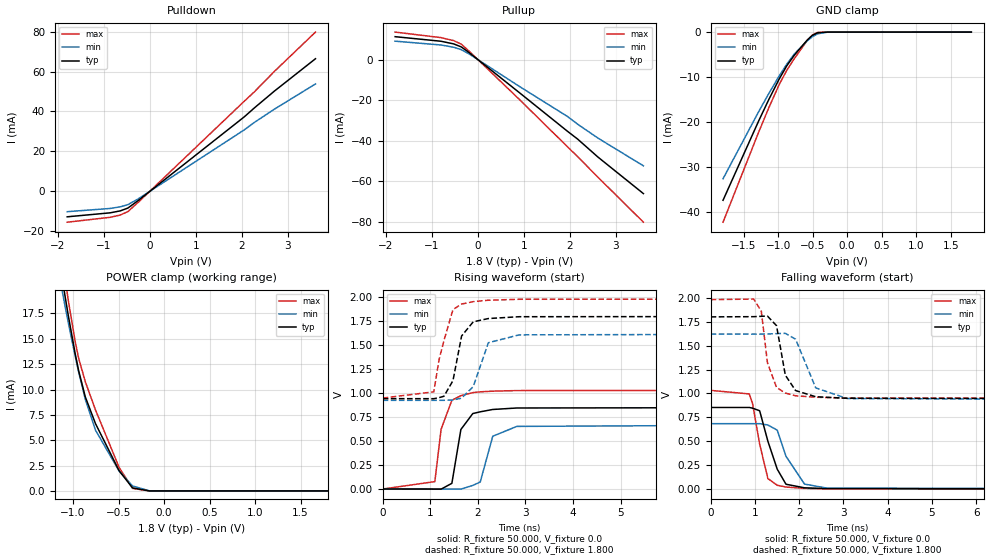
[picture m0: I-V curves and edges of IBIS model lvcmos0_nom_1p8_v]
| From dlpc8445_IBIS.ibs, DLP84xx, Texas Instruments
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|*********************** Begin LVCMOS ***********************************
|   Model Cell1_12
[Model]  lvcmos0_nom_1p8_v
Model_type I/O
Polarity   Non-Inverting
Enable   Active-High
Vinl =  0.580V
Vinh =  1.270V
Vmeas =  0.900V
Cref =  50.000pF
Rref =  1.000M
Vref =  0.0V
C_comp   4.812pF   4.643pF   4.867pF
[Model Spec]
Vinh   1.270V   1.270V   1.270V
Vinl   0.580V   0.580V   0.580V
Vmeas   0.900V   NA   NA
Vref   0.0V   NA   NA
Cref   50.000pF   NA   NA
Rref   1.000M   NA   NA
[Temperature Range]   25.000   0.125k   -40.000
[Voltage Range]   1.800V   1.620V   1.980V
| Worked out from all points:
|   slope of the pulldown table from 0 to 0.27 V, typ, clamps not added: 54.9 ohm
|   slope of the pullup table from 0 to 0.27 V, typ, clamps not added: 55.5 ohm
|   GND clamp passes 1 mA (typ) near -0.53 V on its own axis
|   POWER clamp passes 1 mA (typ) near -0.42 V on its own axis
|   rising waveform, R_fixture 50.000, V_fixture 0.0: 20-80 % time 182ps typ, 226ps min, 212ps max; typ from 0 V to 0.853 V
|   rising waveform, R_fixture 50.000, V_fixture 1.800: 20-80 % time 212ps typ, 265ps min, 259ps max; typ from 0.942 V to 1.8 V
|   falling waveform, R_fixture 50.000, V_fixture 0.0: 20-80 % time 316ps typ, 387ps min, 251ps max; typ from 0.853 V to 0 V
|   falling waveform, R_fixture 50.000, V_fixture 1.800: 20-80 % time 233ps typ, 301ps min, 197ps max; typ from 1.8 V to 0.942 V
[Pulldown]
|Voltage   I(typ)   I(min)   I(max)
-1.8V     -12.84mA   -10.27mA   -15.54mA
-865mV    -10.84mA   -8.642mA   -13.1mA
-645mV    -9.86mA    -7.824mA   -11.94mA
-480mV    -8.448mA   -6.74mA    -10.22mA
-260mV    -4.738mA   -3.909mA   -5.663mA
2.05V     37.29mA    30.77mA    45.13mA
2.27V     41.78mA    34.51mA    49.85mA
2.71V     50.3mA     41.22mA    60.2mA
3.6V      66.47mA    53.82mA    79.83mA
[Pullup]
|Voltage   I(typ)   I(min)   I(max)
-1.8V     11.29mA    9.078mA    13.55mA
-800mV    9.032mA    7.197mA    10.82mA
-525mV    7.725mA    6.075mA    9.333mA
-360mV    6.234mA    4.894mA    7.591mA
-195mV    3.517mA    2.852mA    4.244mA
905mV     -16.31mA   -13.23mA   -19.67mA
1.95V     -35.31mA   -28.02mA   -42.94mA
2.17V     -39.14mA   -31.81mA   -47.78mA
2.61V     -47.96mA   -38.62mA   -57.87mA
3.6V      -65.97mA   -52.3mA    -80.04mA
[GND_clamp]
|Voltage   I(typ)   I(min)   I(max)
-1.8V     -37.47mA   -32.67mA   -42.35mA
-1.282V   -19.75mA   -17.69mA   -22.24mA
-1.134V   -14.95mA   -13.62mA   -16.78mA
-986mV    -10.46mA   -9.778mA   -11.7mA
-875mV    -7.486mA   -7.133mA   -8.501mA
-764mV    -5.097mA   -4.838mA   -5.86mA
-579mV    -1.766mA   -1.945mA   -1.858mA
-505mV    -733.5uA   -1.029mA   -653uA
-431mV    -154.9uA   -383.8uA   -81.65uA
-283mV    -1.21uA    -14.44uA   -257.5nA
1.8V      0A         0A         0A
[POWER_clamp]
|Voltage   I(typ)   I(min)   I(max)
-1.789V   62.42mA    54.67mA    70.27mA
-1.123V   21.2mA     19.93mA    23.18mA
-1.086V   19.15mA    18.18mA    20.87mA
-1.049V   17.17mA    16.48mA    18.65mA
-975mV    13.5mA     13.25mA    14.69mA
-938mV    11.87mA    11.73mA    13.09mA
-864mV    9.251mA    9.016mA    10.75mA
-753mV    6.643mA    5.998mA    7.994mA
-494mV    2mA        1.965mA    2.33mA
-346mV    296uA      492.1uA    251.8uA
-161mV    784nA      8.647uA    252.1nA
1.8V      0A         0A         0A
[Ramp]
| variable   typ   min   max
dV/dt_r   0.512/0.182n   0.411/0.226n   0.619/0.212n
dV/dt_f   0.515/0.233n   0.417/0.300n   0.619/0.197n
R_load = 50.000
[Rising Waveform]
R_fixture= 50.000
V_fixture= 0.0
V_fixture_min= 0.0
V_fixture_max= 0.0
L_fixture= 0.0H
C_fixture= 0.0F
|time   V(typ)   V(min)   V(max)
0s        1.078uV    9.729uV    1.547uV
1.096ns   -782uV     18.33uV    76.96mV
1.227ns   -1.692mV   22.08uV    622.1mV
1.454ns   59.55mV    -910.3uV   925.3mV
1.643ns   620.4mV    -1.351mV   972.7mV
1.894ns   786.7mV    37.36mV    1.005V
2.05ns    804.7mV    73.22mV    1.013V
2.313ns   829mV      550.2mV    1.02V
2.819ns   844.5mV    652.6mV    1.026V
16ns      853.4mV    684.2mV    1.031V
[Rising Waveform]
R_fixture= 50.000
V_fixture= 1.800
V_fixture_min= 1.620
V_fixture_max= 1.980
L_fixture= 0.0H
C_fixture= 0.0F
|time   V(typ)   V(min)   V(max)
0s        941.8mV    924.6mV    948.1mV
1.074ns   941.5mV    924.6mV    1.013V
1.184ns   952.3mV    924.5mV    1.347V
1.287ns   966.8mV    924.6mV    1.548V
1.477ns   1.13V      928mV      1.871V
1.658ns   1.595V     947.1mV    1.928V
1.903ns   1.743V     1.068V     1.953V
2.221ns   1.777V     1.525V     1.968V
2.87ns    1.796V     1.607V     1.978V
16ns      1.8V       1.62V      1.98V
[Falling Waveform]
R_fixture= 50.000
V_fixture= 0.0
V_fixture_min= 0.0
V_fixture_max= 0.0
L_fixture= 0.0H
C_fixture= 0.0F
|time   V(typ)   V(min)   V(max)
0s        853.5mV    684.2mV    1.032V
872ps     853.6mV    684.2mV    994.9mV
947ps     846.3mV    684.2mV    896mV
1.108ns   818.9mV    684.3mV    470.4mV
1.294ns   500.5mV    670.3mV    110.4mV
1.505ns   208.9mV    616.4mV    40.63mV
1.703ns   51.37mV    343.3mV    22.4mV
2.121ns   14.09mV    53.17mV    7.923mV
2.623ns   5.621mV    11.22mV    3.775mV
16ns      23.63uV    47.08uV    11.38uV
[Falling Waveform]
R_fixture= 50.000
V_fixture= 1.800
V_fixture_min= 1.620
V_fixture_max= 1.980
L_fixture= 0.0H
C_fixture= 0.0F
|time   V(typ)   V(min)   V(max)
0s        1.8V       1.62V      1.98V
974ps     1.802V     1.62V      1.986V
1.145ns   1.806V     1.62V      1.86V
1.284ns   1.808V     1.621V     1.32V
1.489ns   1.708V     1.625V     1.063V
1.688ns   1.191V     1.628V     1.004V
1.92ns    1.03V      1.566V     975.7mV
2.375ns   965.5mV    1.058V     960.4mV
3.085ns   949.5mV    946.9mV    951.7mV
16ns      941.8mV    924.6mV    948.1mV
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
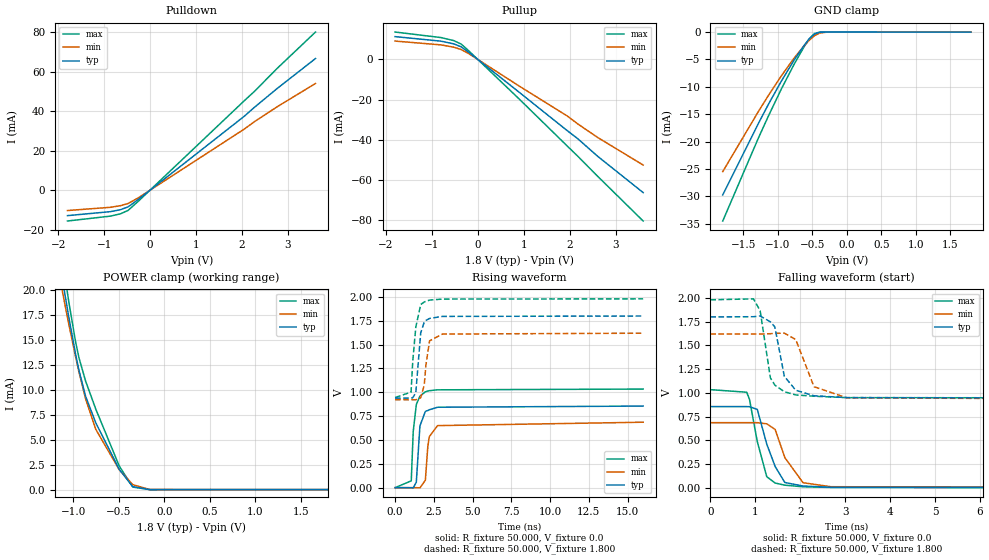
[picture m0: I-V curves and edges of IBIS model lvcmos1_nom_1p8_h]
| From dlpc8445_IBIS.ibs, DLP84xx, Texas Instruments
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|   Model Cell0_12
[Model]  lvcmos1_nom_1p8_h
Model_type I/O
Polarity   Non-Inverting
Enable   Active-High
Vinl =  0.580V
Vinh =  1.270V
Vmeas =  0.900V
Cref =  50.000pF
Rref =  1.000M
Vref =  0.0V
C_comp   5.313pF   5.138pF   5.385pF
[Model Spec]
Vinh   1.270V   1.270V   1.270V
Vinl   0.580V   0.580V   0.580V
Vmeas   0.900V   NA   NA
Vref   0.0V   NA   NA
Cref   50.000pF   NA   NA
Rref   1.000M   NA   NA
[Temperature Range]   25.000   0.125k   -40.000
[Voltage Range]   1.800V   1.620V   1.980V
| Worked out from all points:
|   slope of the pulldown table from 0 to 0.27 V, typ, clamps not added: 54.6 ohm
|   slope of the pullup table from 0 to 0.27 V, typ, clamps not added: 55.2 ohm
|   GND clamp passes 1 mA (typ) near -0.53 V on its own axis
|   POWER clamp passes 1 mA (typ) near -0.42 V on its own axis
|   rising waveform, R_fixture 50.000, V_fixture 0.0: 20-80 % time 211ps typ, 244ps min, 243ps max; typ from 0 V to 0.856 V
|   rising waveform, R_fixture 50.000, V_fixture 1.800: 20-80 % time 252ps typ, 250ps min, 299ps max; typ from 0.939 V to 1.8 V
|   falling waveform, R_fixture 50.000, V_fixture 0.0: 20-80 % time 330ps typ, 410ps min, 275ps max; typ from 0.856 V to 0 V
|   falling waveform, R_fixture 50.000, V_fixture 1.800: 20-80 % time 251ps typ, 328ps min, 207ps max; typ from 1.8 V to 0.939 V
[Pulldown]
|Voltage   I(typ)   I(min)   I(max)
-1.8V     -12.94mA   -10.36mA   -15.67mA
-865mV    -10.92mA   -8.712mA   -13.19mA
-645mV    -9.921mA   -7.883mA   -12.01mA
-480mV    -8.498mA   -6.788mA   -10.28mA
-260mV    -4.765mA   -3.935mA   -5.696mA
2.05V     37.49mA    30.98mA    45.36mA
2.27V     42mA       34.72mA    50.08mA
2.765V    51.55mA    42.28mA    61.75mA
3.6V      66.76mA    54.11mA    80.19mA
[Pullup]
|Voltage   I(typ)   I(min)   I(max)
-1.8V     11.36mA    9.139mA    13.64mA
-800mV    9.085mA    7.243mA    10.88mA
-525mV    7.767mA    6.112mA    9.385mA
-360mV    6.266mA    4.922mA    7.63mA
-195mV    3.534mA    2.867mA    4.265mA
905mV     -16.39mA   -13.3mA    -19.77mA
1.95V     -35.48mA   -28.17mA   -43.14mA
2.17V     -39.32mA   -31.98mA   -48mA
2.61V     -48.19mA   -38.83mA   -58.14mA
3.6V      -66.25mA   -52.54mA   -80.39mA
[GND_clamp]
|Voltage   I(typ)   I(min)   I(max)
-1.8V     -29.72mA   -25.47mA   -34.48mA
-1.282V   -16.66mA   -14.49mA   -19.33mA
-1.134V   -13.12mA   -11.51mA   -15.24mA
-949mV    -8.957mA   -7.99mA    -10.38mA
-764mV    -5.113mA   -4.751mA   -5.884mA
-616mV    -2.396mA   -2.468mA   -2.614mA
-542mV    -1.209mA   -1.466mA   -1.198mA
-468mV    -377uA     -665.7uA   -275.2uA
-394mV    -51.53uA   -194.9uA   -18.39uA
-283mV    -1.21uA    -14.44uA   -257.1nA
1.8V      0A         0A         0A
[POWER_clamp]
|Voltage   I(typ)   I(min)   I(max)
-1.789V   62.53mA    54.94mA    70.53mA
-1.123V   21.33mA    20.06mA    23.4mA
-1.086V   19.29mA    18.31mA    21.08mA
-1.049V   17.31mA    16.6mA     18.84mA
-975mV    13.62mA    13.35mA    14.86mA
-938mV    11.99mA    11.83mA    13.25mA
-864mV    9.348mA    9.1mA      10.88mA
-753mV    6.713mA    6.058mA    8.091mA
-494mV    2.023mA    1.988mA    2.359mA
-346mV    298.7uA    497uA      254.3uA
-161mV    783.7nA    8.652uA    251.7nA
1.8V      0A         0A         0A
[Ramp]
| variable   typ   min   max
dV/dt_r   0.513/0.211n   0.412/0.244n   0.620/0.243n
dV/dt_f   0.516/0.251n   0.419/0.328n   0.621/0.207n
R_load = 50.000
[Rising Waveform]
R_fixture= 50.000
V_fixture= 0.0
V_fixture_min= 0.0
V_fixture_max= 0.0
L_fixture= 0.0H
C_fixture= 0.0F
|time   V(typ)   V(min)   V(max)
0s        1.069uV    9.644uV    1.533uV
1.042ns   -550.6uV   -39.1uV    71.47mV
1.169ns   -2.02mV    38.97uV    590.1mV
1.368ns   57.43mV    -459.9uV   872.2mV
1.601ns   647mV      -1.899mV   959.7mV
1.952ns   800mV      77.75mV    1.005V
2.108ns   808.7mV    428.3mV    1.013V
2.203ns   816.8mV    534.2mV    1.017V
2.74ns    843.4mV    650.7mV    1.026V
16ns      855.7mV    686.4mV    1.034V
[Rising Waveform]
R_fixture= 50.000
V_fixture= 1.800
V_fixture_min= 1.620
V_fixture_max= 1.980
L_fixture= 0.0H
C_fixture= 0.0F
|time   V(typ)   V(min)   V(max)
0s        939.3mV    921.9mV    945.2mV
1.028ns   939mV      921.9mV    1.002V
1.135ns   942mV      921.9mV    1.319V
1.334ns   996.5mV    921.7mV    1.683V
1.653ns   1.624V     942.7mV    1.921V
1.88ns    1.737V     1.077V     1.947V
1.988ns   1.754V     1.288V     1.955V
2.224ns   1.775V     1.54V      1.967V
3.051ns   1.796V     1.611V     1.978V
16ns      1.8V       1.62V      1.98V
[Falling Waveform]
R_fixture= 50.000
V_fixture= 0.0
V_fixture_min= 0.0
V_fixture_max= 0.0
L_fixture= 0.0H
C_fixture= 0.0F
|time   V(typ)   V(min)   V(max)
0s        855.7mV    686.4mV    1.034V
810ps     855.8mV    686.4mV    1.007V
872ps     854.4mV    686.4mV    931.8mV
1.045ns   826.4mV    686.4mV    488.2mV
1.256ns   460.3mV    674.4mV    117.5mV
1.443ns   224.5mV    614.9mV    50.69mV
1.659ns   56.17mV    318mV      28.02mV
2.064ns   19.2mV     54.06mV    11.11mV
2.685ns   6.268mV    11.87mV    4.148mV
16ns      29.74uV    58.99uV    16.59uV
[Falling Waveform]
R_fixture= 50.000
V_fixture= 1.800
V_fixture_min= 1.620
V_fixture_max= 1.980
L_fixture= 0.0H
C_fixture= 0.0F
|time   V(typ)   V(min)   V(max)
0s        1.8V       1.62V      1.98V
960ps     1.802V     1.62V      1.99V
1.109ns   1.81V      1.62V      1.865V
1.337ns   1.748V     1.623V     1.158V
1.436ns   1.695V     1.627V     1.082V
1.647ns   1.175V     1.629V     1.012V
1.901ns   1.028V     1.562V     978.5mV
2.308ns   969.5mV    1.065V     964.9mV
3.037ns   950.4mV    947.8mV    949.9mV
16ns      939.3mV    921.9mV    945.2mV
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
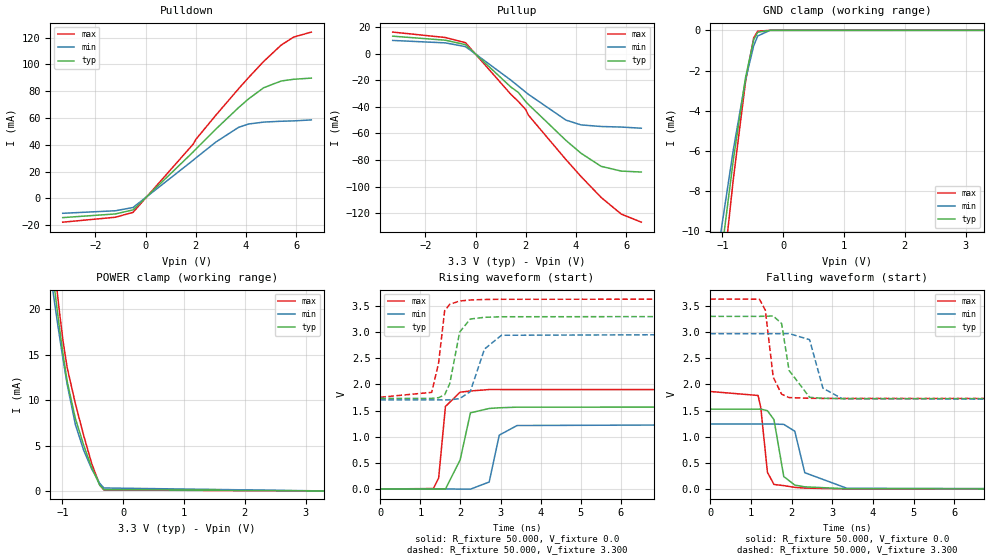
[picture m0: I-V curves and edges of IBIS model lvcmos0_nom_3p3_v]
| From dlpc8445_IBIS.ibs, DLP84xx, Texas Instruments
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|   Model Cell0_12  (lvcmos0_nom_3p3_v)
[Model]  lvcmos0_nom_3p3_v
Model_type I/O
Polarity   Non-Inverting
Enable   Active-High
Vinl =  0.800V
Vinh =  2.000V
Vmeas =  1.650V
Cref =  50.000pF
Rref =  1.000M
Vref =  0.0V
C_comp   3.777pF   3.679pF   3.786pF
[Model Spec]
Vinh   2.000V   2.000V   2.000V
Vinl   0.800V   0.800V   0.800V
Vmeas   1.650V   NA   NA
Vref   0.0V   NA   NA
Cref   50.000pF   NA   NA
Rref   1.000M   NA   NA
[Temperature Range]   25.000   0.125k   -40.000
[Voltage Range]   3.300V   2.970V   3.630V
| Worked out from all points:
|   slope of the pulldown table from 0 to 0.495 V, typ, clamps not added: 55.2 ohm
|   slope of the pullup table from 0 to 0.495 V, typ, clamps not added: 56 ohm
|   GND clamp passes 1 mA (typ) near -0.53 V on its own axis
|   POWER clamp passes 1 mA (typ) near -0.41 V on its own axis
|   rising waveform, R_fixture 50.000, V_fixture 0.0: 20-80 % time 146ps typ, 184ps min, 126ps max; typ from 0 V to 1.57 V
|   rising waveform, R_fixture 50.000, V_fixture 3.300: 20-80 % time 233ps typ, 344ps min, 178ps max; typ from 1.73 V to 3.3 V
|   falling waveform, R_fixture 50.000, V_fixture 0.0: 20-80 % time 183ps typ, 274ps min, 143ps max; typ from 1.53 V to 0 V
|   falling waveform, R_fixture 50.000, V_fixture 3.300: 20-80 % time 197ps typ, 244ps min, 173ps max; typ from 3.3 V to 1.73 V
[Pulldown]
|Voltage   I(typ)   I(min)   I(max)
-3.3V     -14.43mA   -11.2mA    -17.85mA
-1.2V     -11.68mA   -9.31mA    -14.14mA
-500mV    -8.658mA   -6.872mA   -10.51mA
1.9V      34.74mA    28.52mA    40.59mA
2V        36.71mA    30.11mA    43.98mA
2.8V      51.73mA    42.05mA    62.12mA
3.7V      67.72mA    52.98mA    81.78mA
4.1V      74.26mA    55.5mA     90.2mA
4.7V      82.59mA    56.94mA    102.2mA
5.4V      87.66mA    57.58mA    114.5mA
5.9V      88.95mA    57.85mA    120.5mA
6.6V      89.82mA    58.57mA    124.2mA
[Pullup]
|Voltage   I(typ)   I(min)   I(max)
-3.3V     13.04mA    9.833mA    16.11mA
-1.2V     10.02mA    7.999mA    12.03mA
-400mV    6.652mA    5.179mA    8.12mA
1.4V      -25.1mA    -19.92mA   -30.54mA
1.7V      -29.16mA   -24.48mA   -35.98mA
2V        -36.26mA   -29.09mA   -42.12mA
2.1V      -38.15mA   -30.59mA   -46.21mA
3.6V      -65.29mA   -50.02mA   -79.72mA
4.2V      -74.92mA   -53.61mA   -92.4mA
5V        -84.75mA   -54.81mA   -108.1mA
5.8V      -88.3mA    -55.23mA   -120.6mA
6.6V      -89.04mA   -56.1mA    -126.7mA
[GND_clamp]
|Voltage   I(typ)   I(min)   I(max)
-3.3V     -92.25mA   -61.53mA   -135.9mA
-1.29V    -17.92mA   -15.4mA    -21mA
-1.223V   -16.31mA   -14.07mA   -19.04mA
-1.156V   -14.64mA   -12.74mA   -17.03mA
-1.089V   -12.94mA   -11.36mA   -15.03mA
-1.022V   -11.25mA   -9.966mA   -13.05mA
-821mV    -6.443mA   -5.947mA   -7.408mA
-620mV    -2.35mA    -2.459mA   -2.549mA
-486mV    -478.2uA   -770.4uA   -381uA
-419mV    -94.76uA   -279.9uA   -43.05uA
-218mV    -247.6nA   -2.806uA   -222.6nA
3.3V      0A         0A         0A
[POWER_clamp]
|Voltage   I(typ)   I(min)   I(max)
-3.266V   160.8mA    138.4mA    183mA
-1.189V   25.61mA    23.56mA    28.39mA
-1.122V   21.86mA    20.38mA    24.11mA
-1.055V   18.27mA    17.32mA    20.04mA
-988mV    14.94mA    14.4mA     16.4mA
-921mV    12.03mA    11.7mA     13.54mA
-787mV    7.978mA    7.312mA    9.618mA
-653mV    5.091mA    4.523mA    6.167mA
-519mV    2.551mA    2.434mA    3.033mA
-385mV    631.1uA    830.4uA    645.1uA
-318mV    149.6uA    325.9uA    103.4uA
3.3V      0A         0A         0A
[Ramp]
| variable   typ   min   max
dV/dt_r   0.941/0.146n   0.748/0.185n   1.140/0.126n
dV/dt_f   0.945/0.197n   0.760/0.244n   1.139/0.173n
R_load = 50.000
[Rising Waveform]
R_fixture= 50.000
V_fixture= 0.0
V_fixture_min= 0.0
V_fixture_max= 0.0
L_fixture= 0.0H
C_fixture= 0.0F
|time   V(typ)   V(min)   V(max)
0s        2.51uV     11.6uV     3.016uV
1.324ns   -356.5uV   -108uV     8.56mV
1.456ns   -1.554mV   -76.22uV   210.8mV
1.625ns   -2.812mV   4.284uV    1.577V
1.992ns   557.1mV    -1.523mV   1.851V
2.248ns   1.455V     -3.28mV    1.873V
2.716ns   1.539V     133.3mV    1.901V
2.967ns   1.552V     1.029V     1.901V
3.41ns    1.564V     1.213V     1.9V
16ns      1.569V     1.247V     1.9V
[Rising Waveform]
R_fixture= 50.000
V_fixture= 3.300
V_fixture_min= 2.970
V_fixture_max= 3.630
L_fixture= 0.0H
C_fixture= 0.0F
|time   V(typ)   V(min)   V(max)
0s        1.732V     1.703V     1.754V
1.283ns   1.732V     1.703V     1.847V
1.455ns   1.745V     1.703V     2.411V
1.606ns   1.801V     1.703V     3.409V
1.733ns   2.014V     1.703V     3.53V
1.979ns   2.998V     1.727V     3.593V
2.243ns   3.248V     1.86V      3.612V
2.598ns   3.281V     2.674V     3.622V
3.022ns   3.292V     2.938V     3.626V
16ns      3.3V       2.97V      3.63V
[Falling Waveform]
R_fixture= 50.000
V_fixture= 0.0
V_fixture_min= 0.0
V_fixture_max= 0.0
L_fixture= 0.0H
C_fixture= 0.0F
|time   V(typ)   V(min)   V(max)
0s        1.528V     1.244V     1.865V
1.176ns   1.528V     1.244V     1.789V
1.243ns   1.529V     1.244V     1.555V
1.406ns   1.498V     1.244V     322mV
1.567ns   1.328V     1.244V     89.86mV
1.808ns   240.8mV    1.237V     67.61mV
2.079ns   78.11mV    1.107V     34.73mV
2.325ns   44.5mV     314.6mV    20.58mV
3.364ns   7.548mV    16.34mV    4.321mV
16ns      26.1uV     54.9uV     16.38uV
[Falling Waveform]
R_fixture= 50.000
V_fixture= 3.300
V_fixture_min= 2.970
V_fixture_max= 3.630
L_fixture= 0.0H
C_fixture= 0.0F
|time   V(typ)   V(min)   V(max)
0s        3.3V       2.97V      3.63V
1.211ns   3.3V       2.97V      3.627V
1.354ns   3.302V     2.97V      3.418V
1.549ns   3.307V     2.97V      2.137V
1.755ns   3.162V     2.97V      1.814V
1.938ns   2.268V     2.972V     1.749V
2.444ns   1.753V     2.854V     1.735V
2.771ns   1.735V     1.928V     1.733V
3.245ns   1.729V     1.728V     1.732V
16ns      1.725V     1.703V     1.731V
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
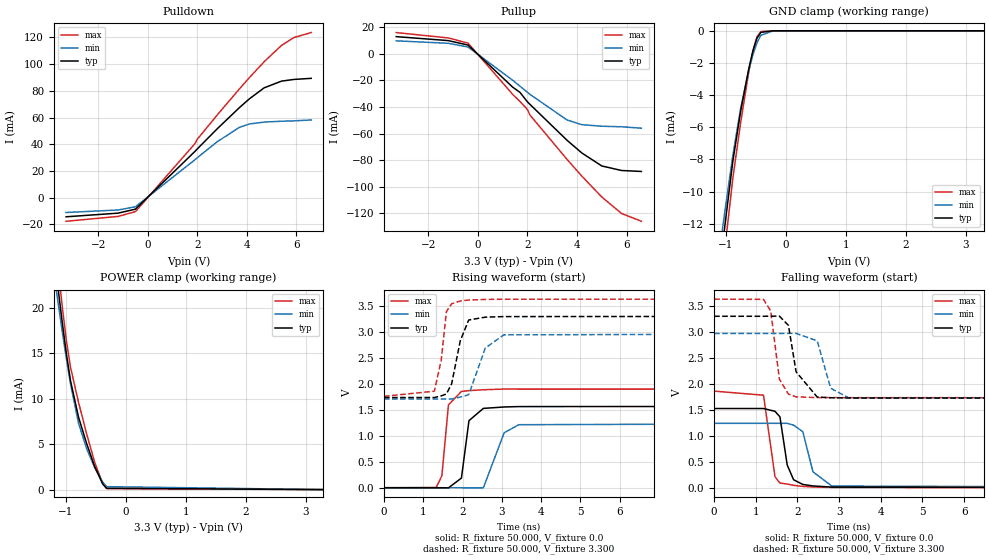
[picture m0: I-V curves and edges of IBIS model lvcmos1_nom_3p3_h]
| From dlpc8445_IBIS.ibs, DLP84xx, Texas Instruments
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|   Model Cell1_12 (lvcmos0_nom_3p3_h)
[Model]  lvcmos1_nom_3p3_h
Model_type I/O
Polarity   Non-Inverting
Enable   Active-High
Vinl =  0.800V
Vinh =  2.000V
Vmeas =  1.650V
Cref =  50.000pF
Rref =  1.000M
Vref =  0.0V
C_comp   3.477pF   3.396pF   3.491pF
[Model Spec]
Vinh   2.000V   2.000V   2.000V
Vinl   0.800V   0.800V   0.800V
Vmeas   1.650V   NA   NA
Vref   0.0V   NA   NA
Cref   50.000pF   NA   NA
Rref   1.000M   NA   NA
[Temperature Range]   25.000   0.125k   -40.000
[Voltage Range]   3.300V   2.970V   3.630V
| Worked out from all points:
|   slope of the pulldown table from 0 to 0.495 V, typ, clamps not added: 55.5 ohm
|   slope of the pullup table from 0 to 0.495 V, typ, clamps not added: 56.3 ohm
|   GND clamp passes 1 mA (typ) near -0.53 V on its own axis
|   POWER clamp passes 1 mA (typ) near -0.41 V on its own axis
|   rising waveform, R_fixture 50.000, V_fixture 0.0: 20-80 % time 146ps typ, 186ps min, 122ps max; typ from 0 V to 1.57 V
|   rising waveform, R_fixture 50.000, V_fixture 3.300: 20-80 % time 267ps typ, 326ps min, 182ps max; typ from 1.74 V to 3.3 V
|   falling waveform, R_fixture 50.000, V_fixture 0.0: 20-80 % time 192ps typ, 269ps min, 143ps max; typ from 1.53 V to 0 V
|   falling waveform, R_fixture 50.000, V_fixture 3.300: 20-80 % time 196ps typ, 244ps min, 171ps max; typ from 3.3 V to 1.73 V
[Pulldown]
|Voltage   I(typ)   I(min)   I(max)
-3.3V     -14.32mA   -11.11mA   -17.7mA
-1.2V     -11.6mA    -9.232mA   -14.04mA
-500mV    -8.607mA   -6.824mA   -10.44mA
1.9V      34.57mA    28.35mA    40.36mA
2V        36.53mA    29.93mA    43.75mA
2.8V      51.5mA     41.81mA    61.82mA
3.7V      67.42mA    52.67mA    81.42mA
4.1V      73.95mA    55.17mA    89.82mA
4.7V      82.24mA    56.59mA    101.8mA
5.4V      87.25mA    57.22mA    114mA
5.9V      88.51mA    57.49mA    119.9mA
6.6V      89.34mA    58.18mA    123.6mA
[Pullup]
|Voltage   I(typ)   I(min)   I(max)
-3.3V     12.95mA    9.779mA    16mA
-1.2V     9.962mA    7.949mA    11.96mA
-400mV    6.618mA    5.149mA    8.078mA
1.4V      -24.98mA   -19.81mA   -30.39mA
1.7V      -29.02mA   -24.35mA   -35.81mA
2V        -36.09mA   -28.93mA   -41.92mA
2.1V      -37.97mA   -30.43mA   -45.99mA
3.6V      -65.01mA   -49.76mA   -79.37mA
4.2V      -74.58mA   -53.26mA   -92.01mA
5V        -84.28mA   -54.42mA   -107.6mA
5.8V      -87.71mA   -54.84mA   -120mA
6.6V      -88.42mA   -55.9mA    -125.9mA
[GND_clamp]
|Voltage   I(typ)   I(min)   I(max)
-3.3V     -114.1mA   -80.88mA   -158.6mA
-1.156V   -16.62mA   -15.01mA   -18.72mA
-1.089V   -14.37mA   -13.14mA   -16.14mA
-1.022V   -12.18mA   -11.28mA   -13.64mA
-888mV    -8.14mA    -7.772mA   -9.194mA
-754mV    -4.947mA   -4.759mA   -5.645mA
-620mV    -2.339mA   -2.447mA   -2.536mA
-553mV    -1.267mA   -1.515mA   -1.267mA
-486mV    -477.2uA   -767.9uA   -380.3uA
-419mV    -94.7uA    -279.4uA   -43.03uA
-218mV    -245.2nA   -2.799uA   -220nA
3.3V      0A         0A         0A
[POWER_clamp]
|Voltage   I(typ)   I(min)   I(max)
-3.266V   165.6mA    138.1mA    194.5mA
-1.189V   25.48mA    23.4mA     28.2mA
-1.122V   21.74mA    20.24mA    23.93mA
-1.055V   18.16mA    17.19mA    19.88mA
-988mV    14.83mA    14.29mA    16.26mA
-921mV    11.95mA    11.61mA    13.44mA
-787mV    7.95mA     7.279mA    9.582mA
-653mV    5.075mA    4.507mA    6.145mA
-519mV    2.545mA    2.428mA    3.024mA
-385mV    630.2uA    829uA      644.1uA
-318mV    149.6uA    325.6uA    103.3uA
3.3V      0A         0A         0A
[Ramp]
| variable   typ   min   max
dV/dt_r   0.940/0.146n   0.746/0.187n   1.139/0.122n
dV/dt_f   0.943/0.196n   0.757/0.244n   1.137/0.172n
R_load = 50.000
[Rising Waveform]
R_fixture= 50.000
V_fixture= 0.0
V_fixture_min= 0.0
V_fixture_max= 0.0
L_fixture= 0.0H
C_fixture= 0.0F
|time   V(typ)   V(min)   V(max)
0s        2.541uV    11.85uV    3.103uV
1.326ns   -445uV     -16.52uV   3.549mV
1.474ns   -1.635mV   -103.4uV   228.6mV
1.642ns   -2.598mV   3.263uV    1.595V
1.972ns   185.5mV    -1.211mV   1.853V
2.164ns   1.291V     -1.915mV   1.869V
2.53ns    1.527V     -1.5mV     1.886V
3.06ns    1.554V     1.058V     1.899V
3.432ns   1.562V     1.213V     1.898V
16ns      1.566V     1.243V     1.898V
[Rising Waveform]
R_fixture= 50.000
V_fixture= 3.300
V_fixture_min= 2.970
V_fixture_max= 3.630
L_fixture= 0.0H
C_fixture= 0.0F
|time   V(typ)   V(min)   V(max)
0s        1.736V     1.708V     1.759V
1.282ns   1.736V     1.708V     1.858V
1.456ns   1.767V     1.707V     2.445V
1.59ns    1.805V     1.708V     3.39V
1.723ns   2V         1.707V     3.54V
1.943ns   2.829V     1.746V     3.595V
2.157ns   3.228V     1.789V     3.612V
2.58ns    3.283V     2.689V     3.624V
3.051ns   3.294V     2.942V     3.628V
16ns      3.3V       2.97V      3.63V
[Falling Waveform]
R_fixture= 50.000
V_fixture= 0.0
V_fixture_min= 0.0
V_fixture_max= 0.0
L_fixture= 0.0H
C_fixture= 0.0F
|time   V(typ)   V(min)   V(max)
0s        1.526V     1.241V     1.861V
1.186ns   1.526V     1.241V     1.782V
1.462ns   1.472V     1.241V     213.4mV
1.58ns    1.366V     1.241V     92.02mV
1.755ns   439.3mV    1.241V     74.2mV
1.908ns   156.2mV    1.206V     48.21mV
2.13ns    65.18mV    1.08V      28.03mV
2.372ns   37.25mV    310mV      16.32mV
2.823ns   14.64mV    35.14mV    7.544mV
16ns      23.35uV    46.91uV    15.53uV
[Falling Waveform]
R_fixture= 50.000
V_fixture= 3.300
V_fixture_min= 2.970
V_fixture_max= 3.630
L_fixture= 0.0H
C_fixture= 0.0F
|time   V(typ)   V(min)   V(max)
0s        3.3V       2.97V      3.63V
1.186ns   3.3V       2.97V      3.625V
1.36ns    3.302V     2.97V      3.399V
1.566ns   3.303V     2.97V      2.093V
1.784ns   3.125V     2.971V     1.804V
1.968ns   2.232V     2.971V     1.75V
2.474ns   1.747V     2.828V     1.736V
2.799ns   1.733V     1.915V     1.736V
3.235ns   1.729V     1.729V     1.735V
16ns      1.728V     1.708V     1.735V
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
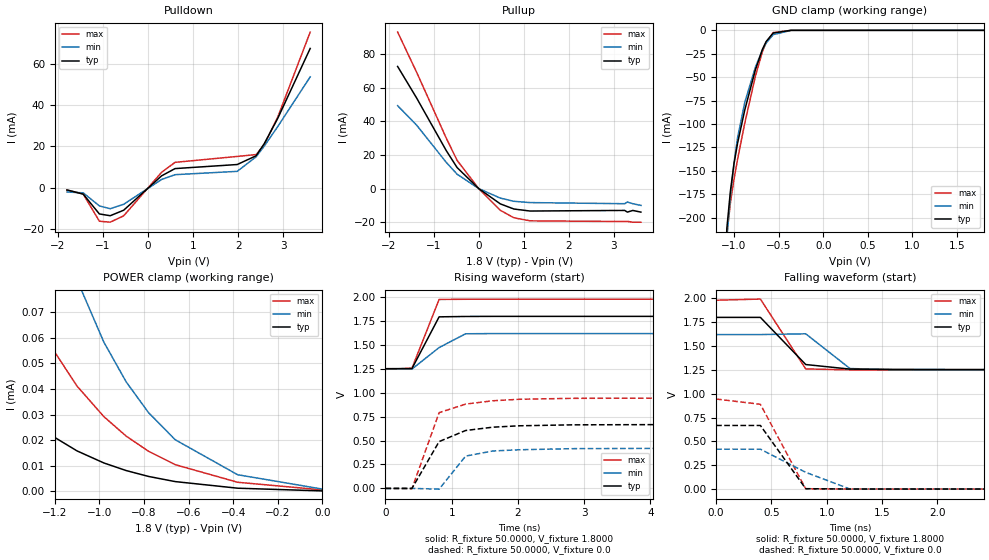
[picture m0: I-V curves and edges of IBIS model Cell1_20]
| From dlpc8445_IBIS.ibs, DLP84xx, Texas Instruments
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|   Model Cell1_20
[Model]  Cell1_20
Model_type I/O
Polarity   Non-Inverting
Enable   Active-Low
Vinl =   0.6300V
Vinh =   1.1700V
Vmeas =  0.9000V
Cref =   50.0000pF
Rref =   1.0000M
Vref =   0.0V
C_comp   1.0153pF   1.0049pF   1.1914pF
[Model Spec]
Vinl 0.63V 0.567V 0.693V
Vinh 1.17V 1.053V 1.287V
[Temperature Range]   25.0000   0.1250k   -40.0000
[Voltage Range]   1.8000V   1.6200V   1.9800V
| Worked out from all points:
|   slope of the pulldown table from 0 to 0.27 V, typ, clamps not added: 51.1 ohm
|   slope of the pullup table from 0 to 0.27 V, typ, clamps not added: 48.4 ohm
|   GND clamp passes 1 mA (typ) near -0.52 V on its own axis
|   rising waveform, R_fixture 50.0000, V_fixture 1.8000: 20-80 % time 249ps typ, 476ps min, 251ps max; typ from 1.25 V to 1.8 V
|   rising waveform, R_fixture 50.0000, V_fixture 0.0: 20-80 % time 452ps typ, 291ps min, 292ps max; typ from 0 V to 0.668 V
|   falling waveform, R_fixture 50.0000, V_fixture 1.8000: 20-80 % time 273ps typ, 245ps min, 247ps max; typ from 1.8 V to 1.25 V
|   falling waveform, R_fixture 50.0000, V_fixture 0.0: 20-80 % time 248ps typ, 480ps min, 262ps max; typ from 0.668 V to 0 V
[Pulldown]
|Voltage   I(typ)   I(min)   I(max)
-1.8V     -1mA       -2mA       -1mA
-1.44V    -3mA       -2.4mA     -3mA
-1.08V    -12.6mA    -8.7mA     -16.1mA
-840mV    -13.46mA   -10.08mA   -16.58mA
-540mV    -10.79mA   -7.914mA   -13.49mA
300mV     5.805mA    4.046mA    7.496mA
600mV     9.317mA    6.377mA    12.33mA
1.98V     11.28mA    7.981mA    15.19mA
2.4V      15.51mA    15.04mA    16.09mA
2.58V     21.37mA    20.18mA    20.86mA
2.88V     33.61mA    29.64mA    34.23mA
3.6V      67.38mA    53.63mA    75.26mA
[Pullup]
|Voltage   I(typ)   I(min)   I(max)
-1.8V     72.69mA    49.35mA    93.16mA
-1.38V    54mA       37.81mA    69.35mA
-720mV    22.59mA    15.59mA    30.01mA
-480mV    12.53mA    8.566mA    16.81mA
0V        100pA      2.1nA      100pA
480mV     -9.109mA   -5.667mA   -12.93mA
780mV     -12.15mA   -7.562mA   -17.36mA
1.14V     -13.36mA   -8.33mA    -19.2mA
3.24V     -13mA      -9mA       -19.6mA
3.3V      -14mA      -8mA       -19.5mA
3.42V     -13mA      -9mA       -20mA
3.6V      -14mA      -10mA      -20mA
[GND_clamp]
|Voltage   I(typ)   I(min)   I(max)
-1.8V     -2.02A     -1.813A    -2.236A
-1.08V    -211.4mA   -221.7mA   -217.8mA
-1.04V    -171.5mA   -176.7mA   -183.9mA
-1V       -142.6mA   -141.5mA   -159mA
-960mV    -120.6mA   -114.8mA   -137.8mA
-880mV    -85.31mA   -77.31mA   -99.44mA
-760mV    -42.13mA   -39.29mA   -48.93mA
-680mV    -20.03mA   -20.65mA   -22.41mA
-640mV    -12.03mA   -13.63mA   -12.86mA
-560mV    -2.846mA   -4.595mA   -2.424mA
-360mV    -5.013uA   -51.09uA   -891.9nA
1.8V      176.9nA    2.491uA    194.3nA
[POWER_clamp]
|Voltage   I(typ)   I(min)   I(max)
-1.8V     83.81uA    422.8uA    210.7uA
-1.78V    80.5uA     406.5uA    202.5uA
-1.56V    50.38uA    257.6uA    127.7uA
-1.36V    31.45uA    162.5uA    80.45uA
-1.24V    23.15uA    120.3uA    59.65uA
-1.1V     15.79uA    82.54uA    41.09uA
-980mV    11.1uA     58.29uA    29.2uA
-880mV    8.125uA    42.78uA    21.59uA
-780mV    5.835uA    30.79uA    15.68uA
-660mV    3.816uA    20.16uA    10.43uA
-380mV    1.235uA    6.497uA    3.553uA
0V        176.9nA    893nA      569.1nA
[Ramp]
| variable   typ   min   max
dV/dt_r  0.4006/0.4444n   0.2515/0.2909n   0.5667/0.2851n
dV/dt_f  0.3288/0.2662n   0.2232/0.2453n   0.4410/0.2410n
R_load = 50.0000
[Rising Waveform]
R_fixture= 50.0000
V_fixture= 1.8000
V_fixture_min= 1.6200
V_fixture_max= 1.9800
L_fixture= 0.0H
C_fixture= 0.0F
|time   V(typ)   V(min)   V(max)
0s        1.252V     1.248V     1.245V
400ps     1.253V     1.248V     1.257V
810ps     1.794V     1.473V     1.976V
1.21ns    1.798V     1.617V     1.978V
1.62ns    1.799V     1.619V     1.979V
40ns      1.8V       1.62V      1.98V
[Rising Waveform]
R_fixture= 50.0000
V_fixture= 0.0
V_fixture_min= 0.0
V_fixture_max= 0.0
L_fixture= 0.0H
C_fixture= 0.0F
|time   V(typ)   V(min)   V(max)
0s        1.303uV    5.428uV    1.468uV
400ps     -4.347uV   2.126uV    -3.051mV
810ps     489.6mV    -8.041mV   792.1mV
1.21ns    605.5mV    337.8mV    881.5mV
1.62ns    640.1mV    391.3mV    916.3mV
2.02ns    654.7mV    404mV      932mV
2.83ns    664.8mV    415.7mV    941.9mV
4.44ns    667.5mV    419mV      944.3mV
40ns      667.6mV    419.2mV    944.5mV
[Falling Waveform]
R_fixture= 50.0000
V_fixture= 1.8000
V_fixture_min= 1.6200
V_fixture_max= 1.9800
L_fixture= 0.0H
C_fixture= 0.0F
|time   V(typ)   V(min)   V(max)
0s        1.8V       1.62V      1.98V
400ps     1.8V       1.62V      1.992V
810ps     1.306V     1.628V     1.26V
1.21ns    1.258V     1.264V     1.25V
1.62ns    1.255V     1.251V     1.247V
3.23ns    1.253V     1.248V     1.245V
40ns      1.252V     1.248V     1.245V
[Falling Waveform]
R_fixture= 50.0000
V_fixture= 0.0
V_fixture_min= 0.0
V_fixture_max= 0.0
L_fixture= 0.0H
C_fixture= 0.0F
|time   V(typ)   V(min)   V(max)
0s        667.6mV    419.2mV    944.5mV
400ps     667.5mV    419.2mV    889.5mV
810ps     5.061mV    176.1mV    3.729mV
1.21ns    1.33mV     1.684mV    1.336mV
40ns      -9.331uV   -9.888uV   -13.46uV
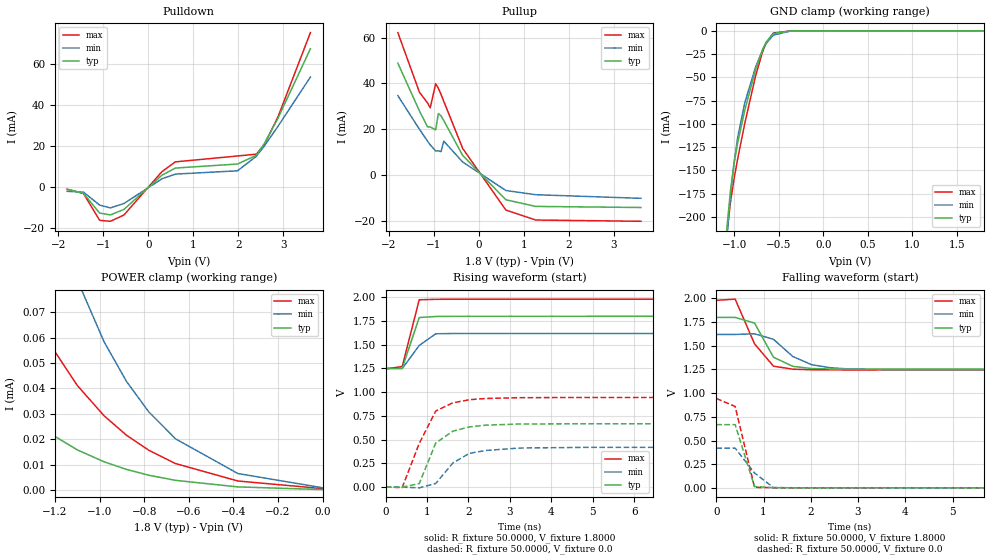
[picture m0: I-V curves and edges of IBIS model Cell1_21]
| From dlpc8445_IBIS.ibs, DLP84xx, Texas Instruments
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|   Model Cell1_21
[Model]  Cell1_21
Model_type I/O
Polarity   Non-Inverting
Enable   Active-Low
Vinl =   0.6300V
Vinh =   1.1700V
Vmeas =  0.9000V
Cref =   50.0000pF
Rref =   1.0000M
Vref =   0.0V
C_comp   1.0153pF   1.0049pF   1.1914pF
[Model Spec]
Vinl 0.63V 0.567V 0.693V
Vinh 1.17V 1.053V 1.287V
[Temperature Range]   25.0000   0.1250k   -40.0000
[Voltage Range]   1.8000V   1.6200V   1.9800V
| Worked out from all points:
|   slope of the pulldown table from 0 to 0.27 V, typ, clamps not added: 51.1 ohm
|   slope of the pullup table from 0 to 0.27 V, typ, clamps not added: 48.4 ohm
|   GND clamp passes 1 mA (typ) near -0.52 V on its own axis
|   rising waveform, R_fixture 50.0000, V_fixture 1.8000: 20-80 % time 253ps typ, 459ps min, 257ps max; typ from 1.25 V to 1.8 V
|   rising waveform, R_fixture 50.0000, V_fixture 0.0: 20-80 % time 538ps typ, 646ps min, 585ps max; typ from 0 V to 0.668 V
|   falling waveform, R_fixture 50.0000, V_fixture 1.8000: 20-80 % time 423ps typ, 654ps min, 490ps max; typ from 1.8 V to 1.25 V
|   falling waveform, R_fixture 50.0000, V_fixture 0.0: 20-80 % time 251ps typ, 470ps min, 272ps max; typ from 0.668 V to 0 V
[Pulldown]
|Voltage   I(typ)   I(min)   I(max)
-1.8V     -1mA       -2mA       -1mA
-1.44V    -3mA       -2.4mA     -3mA
-1.08V    -12.6mA    -8.7mA     -16.1mA
-840mV    -13.46mA   -10.08mA   -16.58mA
-540mV    -10.79mA   -7.914mA   -13.49mA
300mV     5.805mA    4.046mA    7.496mA
600mV     9.317mA    6.377mA    12.33mA
1.98V     11.28mA    7.98mA     15.19mA
2.4V      15.51mA    15.04mA    16.09mA
2.58V     21.36mA    20.17mA    20.86mA
2.88V     33.6mA     29.62mA    34.22mA
3.6V      67.35mA    53.6mA     75.23mA
[Pullup]
|Voltage   I(typ)   I(min)   I(max)
-1.8V     48.86mA    34.71mA    62.15mA
-1.32V    28.03mA    20.05mA    36.19mA
-1.14V    21.11mA    14.9mA     31.53mA
-1.08V    21.04mA    13.29mA    29.4mA
-960mV    19.79mA    10.59mA    39.89mA
-900mV    26.92mA    10.65mA    37.91mA
-840mV    25.88mA    10.32mA    35.23mA
-780mV    23.86mA    14.89mA    32.26mA
-360mV    8.671mA    5.807mA    11.73mA
600mV     -10.63mA   -6.602mA   -15.13mA
1.26V     -13.52mA   -8.425mA   -19.44mA
3.6V      -14mA      -10mA      -20mA
[GND_clamp]
|Voltage   I(typ)   I(min)   I(max)
-1.8V     -2.02A     -1.813A    -2.236A
-1.08V    -211.4mA   -221.7mA   -217.8mA
-1.04V    -171.5mA   -176.7mA   -183.9mA
-1V       -142.6mA   -141.5mA   -159mA
-960mV    -120.6mA   -114.8mA   -137.8mA
-880mV    -85.31mA   -77.31mA   -99.44mA
-760mV    -42.13mA   -39.29mA   -48.93mA
-680mV    -20.03mA   -20.65mA   -22.41mA
-640mV    -12.03mA   -13.63mA   -12.86mA
-560mV    -2.846mA   -4.595mA   -2.424mA
-360mV    -5.013uA   -51.09uA   -891.9nA
1.8V      176.9nA    2.491uA    194.3nA
[POWER_clamp]
|Voltage   I(typ)   I(min)   I(max)
-1.8V     83.81uA    422.8uA    210.7uA
-1.78V    80.5uA     406.5uA    202.5uA
-1.56V    50.38uA    257.6uA    127.7uA
-1.36V    31.45uA    162.5uA    80.45uA
-1.24V    23.15uA    120.3uA    59.65uA
-1.1V     15.79uA    82.54uA    41.09uA
-980mV    11.1uA     58.29uA    29.2uA
-880mV    8.125uA    42.78uA    21.59uA
-780mV    5.835uA    30.79uA    15.68uA
-660mV    3.816uA    20.16uA    10.43uA
-380mV    1.235uA    6.497uA    3.553uA
0V        176.9nA    893nA      569.1nA
[Ramp]
| variable   typ   min   max
dV/dt_r  0.4006/0.5327n   0.2515/0.6384n   0.5667/0.5794n
dV/dt_f  0.3288/0.4208n   0.2232/0.6456n   0.4410/0.4831n
R_load = 50.0000
[Rising Waveform]
R_fixture= 50.0000
V_fixture= 1.8000
V_fixture_min= 1.6200
V_fixture_max= 1.9800
L_fixture= 0.0H
C_fixture= 0.0F
|time   V(typ)   V(min)   V(max)
0s        1.252V     1.248V     1.245V
400ps     1.253V     1.248V     1.27V
810ps     1.786V     1.492V     1.973V
1.21ns    1.797V     1.615V     1.978V
1.62ns    1.799V     1.618V     1.979V
40ns      1.8V       1.62V      1.98V
[Rising Waveform]
R_fixture= 50.0000
V_fixture= 0.0
V_fixture_min= 0.0
V_fixture_max= 0.0
L_fixture= 0.0H
C_fixture= 0.0F
|time   V(typ)   V(min)   V(max)
0s        1.303uV    5.428uV    1.469uV
400ps     -4.824uV   2.108uV    -4.58mV
810ps     36.51mV    -7.758mV   459.6mV
1.21ns    464.8mV    38.88mV    801.8mV
1.62ns    588.9mV    253mV      887.4mV
2.02ns    634.2mV    355.2mV    920.3mV
2.42ns    652.8mV    386mV      933.4mV
3.23ns    664.6mV    411.7mV    942.1mV
4.85ns    667.4mV    418.8mV    944.4mV
40ns      667.6mV    419.2mV    944.5mV
[Falling Waveform]
R_fixture= 50.0000
V_fixture= 1.8000
V_fixture_min= 1.6200
V_fixture_max= 1.9800
L_fixture= 0.0H
C_fixture= 0.0F
|time   V(typ)   V(min)   V(max)
0s        1.8V       1.62V      1.98V
400ps     1.8V       1.62V      1.993V
810ps     1.74V      1.627V     1.521V
1.21ns    1.38V      1.569V     1.285V
1.62ns    1.283V     1.387V     1.253V
2.02ns    1.26V      1.3V       1.247V
2.42ns    1.255V     1.268V     1.246V
2.83ns    1.253V     1.255V     1.245V
3.64ns    1.253V     1.249V     1.245V
40ns      1.252V     1.248V     1.245V
[Falling Waveform]
R_fixture= 50.0000
V_fixture= 0.0
V_fixture_min= 0.0
V_fixture_max= 0.0
L_fixture= 0.0H
C_fixture= 0.0F
|time   V(typ)   V(min)   V(max)
0s        667.6mV    419.2mV    944.5mV
400ps     667.5mV    419.2mV    859.3mV
810ps     13.7mV     157mV      5.405mV
1.21ns    1.852mV    3.57mV     1.494mV
1.62ns    795.6uV    1.24mV     712.9uV
40ns      -6.025uV   3.033uV    -15.54uV
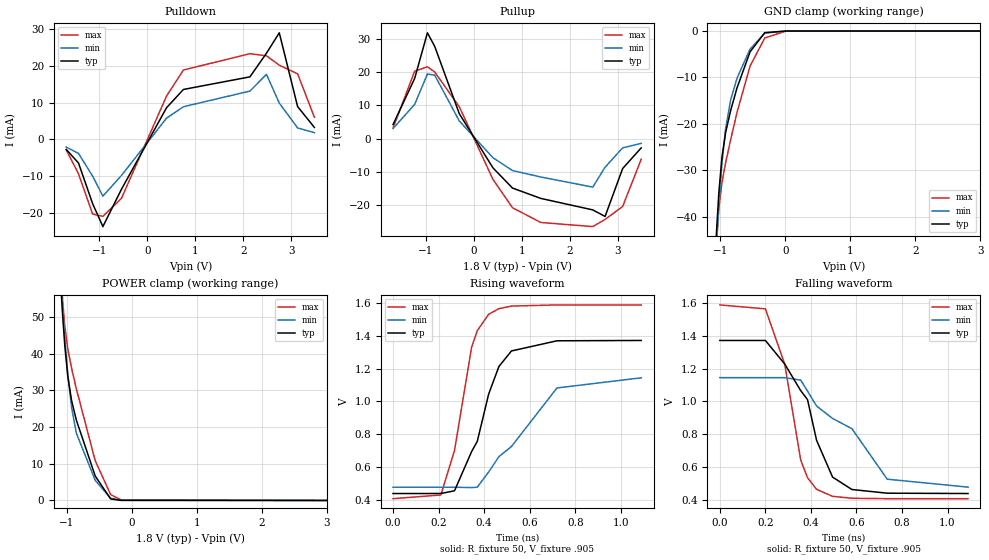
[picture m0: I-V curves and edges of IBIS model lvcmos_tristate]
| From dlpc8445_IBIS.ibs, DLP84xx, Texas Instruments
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|   MODEL lvcmos_tristate
[Model] lvcmos_tristate
Model_type 3-state
|C_comp_off 0. 0. 0.
|C_comp_on 0. 0. 0.
C_comp 0.00000001f 0.00000001f 0.00000001f
Vmeas = 0.9
Vref = 0.9V
Rref = 25
Cref = 10pF
[Model Spec]
[Temperature Range]  40 150 -40
[Voltage Range] 1.8 1.62 1.98
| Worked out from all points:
|   slope of the pulldown table from 0 to 0.27 V, typ, clamps not added: 44.8 ohm
|   slope of the pullup table from 0 to 0.27 V, typ, clamps not added: 43.5 ohm
|   GND clamp passes 1 mA (typ) near -0.38 V on its own axis
|   POWER clamp passes 1 mA (typ) near -0.37 V on its own axis
|   rising waveform, R_fixture 50, V_fixture .905: 20-80 % time 138ps typ, 225ps min, 94.3ps max; typ from 0.438 V to 1.37 V
|   falling waveform, R_fixture 50, V_fixture .905: 20-80 % time 160ps typ, 255ps min, 113ps max; typ from 1.37 V to 0.438 V
[Pulldown]
-1.692V   -2.729mA   -2.083mA   -2.847mA
-1.436V   -6.421mA   -3.811mA   -9.354mA
-1.143V   -17.4mA    -9.962mA   -20.25mA
-928.3mV  -23.67mA   -15.41mA   -20.9mA
-541.3mV  -13.55mA   -9.791mA   -16mA
399.9mV   8.606mA    5.774mA    11.78mA
750.3mV   13.54mA    8.847mA    18.81mA
2.136V    16.96mA    13.1mA     23.25mA
2.481V    23.37mA    17.64mA    22.67mA
2.748V    28.91mA    9.846mA    20.13mA
3.13V     8.899mA    3.103mA    17.79mA
3.48V     3.235mA    1.813mA    5.99mA
[Pullup]
-1.68V    4.214mA    3.017mA    3.175mA
-1.23V    18.13mA    10.3mA     20.32mA
-963.5mV  31.93mA    19.47mA    21.67mA
-811.8mV  27.84mA    19.16mA    20.09mA
-299.4mV  7.498mA    5.309mA    9.587mA
401.3mV   -8.853mA   -5.802mA   -12.32mA
809.2mV   -14.97mA   -9.678mA   -20.92mA
1.4V      -18.1mA    -11.63mA   -25.37mA
2.483V    -21.57mA   -14.68mA   -26.61mA
2.739V    -23.54mA   -8.672mA   -24.44mA
3.105V    -9.073mA   -2.815mA   -20.55mA
3.492V    -2.827mA   -1.479mA   -6.276mA
[GND Clamp]
-1.692V   -334.5mA   -288.2mA   -358.7mA
-1.069V   -45.45mA   -48.31mA   -47.45mA
-1.062V   -43.6mA    -46.55mA   -45.71mA
-1.025V   -34.89mA   -37.7mA    -38.29mA
-977.6mV  -27.3mA    -28.64mA   -32.71mA
-920.1mV  -21.84mA   -20.97mA   -28.36mA
-842.3mV  -17.08mA   -14.8mA    -23.38mA
-744.1mV  -12.21mA   -10.12mA   -17.49mA
-544.4mV  -4.478mA   -3.897mA   -7.555mA
-317.7mV  -348.2uA   -465.5uA   -1.493mA
12.21mV   0A         0A         0A
3.48V     0A         0A         0A
[Power Clamp]
-1.692V   339.7mA    294.8mA    369.8mA
-1.085V   56.4mA     58.43mA    60.03mA
-1.078V   54.39mA    56.54mA    58.1mA
-1.065V   50.6mA     52.9mA     54.61mA
-1.032V   42.33mA    44.47mA    47.61mA
-985.7mV  33.89mA    34.56mA    41.35mA
-926.3mV  27.18mA    25.3mA     35.99mA
-853.7mV  21.91mA    18.34mA    30.44mA
-563.3mV  6.664mA    5.479mA    10.85mA
-325.7mV  421.7uA    613.2uA    1.606mA
-167.4mV  40.17uA    38.63uA    165.6uA
3.492V    0A         0A         0A
[Ramp]
dV/dt_r .561/137.902p .401/225.31p .71/94.36p
dV/dt_f .561/160.176p .401/255.673p .71/112.721p
[Rising Waveform]
R_fixture = 50
V_fixture = .905
V_fixture_min = .81
V_fixture_max = .997
0s        437.6mV    476.1mV    406mV
210ps     437.7mV    476.1mV    428.8mV
270ps     454.3mV    476.1mV    700.4mV
345ps     693.4mV    473.8mV    1.33V
370ps     756.2mV    476.5mV    1.432V
420ps     1.045V     569mV      1.532V
465ps     1.213V     662.8mV    1.566V
520ps     1.308V     724.5mV    1.582V
720ps     1.37V      1.082V     1.589V
1.09ns    1.372V     1.144V     1.589V
[Falling Waveform]
R_fixture = 50
V_fixture = .905
V_fixture_min = .81
V_fixture_max = .997
0s        1.372V     1.145V     1.589V
200ps     1.372V     1.145V     1.565V
285ps     1.228V     1.145V     1.227V
355ps     1.066V     1.13V      642mV
385ps     1.011V     1.063V     534mV
425ps     761.9mV    971.5mV    463mV
495ps     537.9mV    896mV      420.4mV
580ps     462.1mV    833.5mV    408.6mV
735ps     439.6mV    525.2mV    406.1mV
1.09ns    437.6mV    476.6mV    406mV
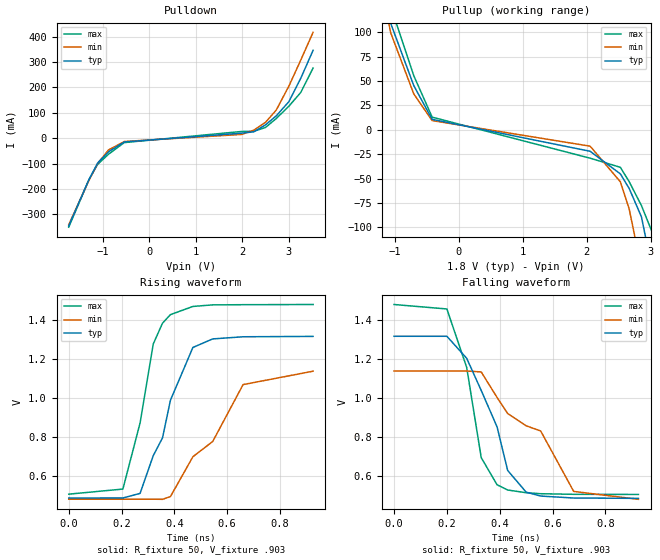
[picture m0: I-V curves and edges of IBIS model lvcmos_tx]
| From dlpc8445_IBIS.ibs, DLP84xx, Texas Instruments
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|   MODEL lvcmos_tx
[Model] lvcmos_tx
Model_type Output
C_comp 1.034p 1.029p 1.051p
Vmeas = 0.9
Cref = 5pF
[Model Spec]
|  Subparameter   typ   min   max
Vmeas   0.9   0.81   0.99
[Temperature Range]  25 125 -40
[Voltage Range] 1.8 1.62 1.98
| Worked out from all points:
|   slope of the pulldown table from 0 to 0.27 V, typ, clamps not added: 57.6 ohm
|   slope of the pullup table from 0 to 0.27 V, typ, clamps not added: 57 ohm
|   rising waveform, R_fixture 50, V_fixture .903: 20-80 % time 114ps typ, 192ps min, 85ps max; typ from 0.487 V to 1.32 V
|   falling waveform, R_fixture 50, V_fixture .903: 20-80 % time 137ps typ, 231ps min, 99ps max; typ from 1.32 V to 0.487 V
[Pulldown]
-1.731V   -345.8mA   -341.1mA   -350.8mA
-1.296V   -163.2mA   -165.8mA   -163.6mA
-1.11V    -97.92mA   -99.65mA   -103.4mA
-876.1mV  -53.71mA   -46.52mA   -63.31mA
-536.3mV  -14.98mA   -13.2mA    -17.52mA
1.986V    19.55mA    14.65mA    26.35mA
2.246V    24.87mA    31.46mA    27.03mA
2.496V    52.06mA    62.1mA     41.87mA
2.729V    87.92mA    110.8mA    77.26mA
3V        143.9mA    205.2mA    126mA
3.255V    236mA      307.5mA    180.1mA
3.52V     346.1mA    417mA      276.3mA
[Pullup]
-1.72V    349.3mA    346mA      351.8mA
-1.333V   189.7mA    190.1mA    194.6mA
-1.062V   109.1mA    99.37mA    126.4mA
-701mV    45.21mA    36.66mA    55.35mA
-414.2mV  10.64mA    9.367mA    12.91mA
2.055V    -22.07mA   -16.84mA   -29.15mA
2.527V    -45.21mA   -53.35mA   -38.49mA
2.665V    -60.16mA   -81.18mA   -53.18mA
2.857V    -89.32mA   -142.5mA   -77.75mA
3.117V    -173.2mA   -243.6mA   -120.1mA
3.26V     -230.7mA   -302.1mA   -165.6mA
3.531V    -344.5mA   -413.8mA   -276mA
[Ramp]
dV/dt_r .499/114.113p .395/192.241p .585/85.148p
dV/dt_f .499/137.232p .395/231.729p .585/98.863p
[Rising Waveform]
R_fixture = 50
V_fixture = .903
V_fixture_min = .81
V_fixture_max = .994
|SiSoft Vcm .903 .81 .994
0s        486.8mV    480.7mV    506.5mV
205ps     486.9mV    480.7mV    532.7mV
270ps     510.4mV    480.7mV    872.7mV
320ps     704.8mV    480.6mV    1.279V
355ps     796.3mV    479.9mV    1.386V
385ps     989.9mV    494mV      1.43V
470ps     1.261V     699.1mV    1.472V
545ps     1.305V     777.4mV    1.48V
660ps     1.316V     1.07V      1.481V
925ps     1.318V     1.139V     1.482V
[Falling Waveform]
R_fixture = 50
V_fixture = .903
V_fixture_min = .81
V_fixture_max = .994
|SiSoft Vcm .903 .81 .994
0s        1.318V     1.14V      1.481V
200ps     1.318V     1.14V      1.458V
275ps     1.205V     1.14V      1.158V
330ps     1.04V      1.135V     695.4mV
390ps     853mV      1.004V     556.2mV
430ps     629.9mV    922mV      529.5mV
500ps     518.6mV    858.9mV    515.5mV
555ps     498.4mV    832.4mV    510.4mV
680ps     488.3mV    522.2mV    507.3mV
925ps     486.7mV    481.6mV    506.6mV
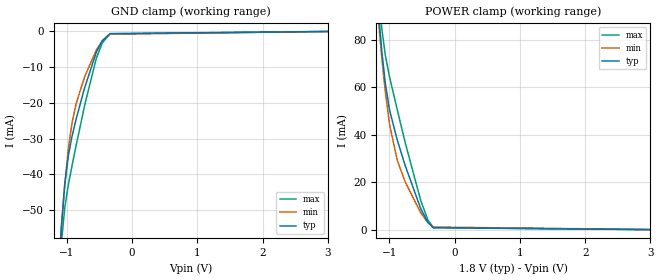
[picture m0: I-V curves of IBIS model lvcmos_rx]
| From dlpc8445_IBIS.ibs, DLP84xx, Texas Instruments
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|   MODEL lvcmos_rx
[Model] lvcmos_rx
Model_type Input
C_comp 1.361p 1.405p 1.304p
Vinl = 0.54
Vinh = 1.26
[Model Spec]
[Temperature Range]  40 150 -40
[Voltage Range] 1.8 1.62 1.98
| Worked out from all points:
|   GND clamp passes 1 mA (typ) near -0.37 V on its own axis
|   POWER clamp passes 1 mA (typ) near -0.33 V on its own axis
[GND Clamp]
-1.756V   -367.7mA   -315.9mA   -439.3mA
-1.104V   -60.35mA   -60.53mA   -64.89mA
-1.084V   -54.46mA   -54.94mA   -59.13mA
-1.032V   -42.83mA   -42.73mA   -49.29mA
-975.7mV  -34.62mA   -32.52mA   -42.72mA
-919.3mV  -29.22mA   -25.48mA   -37.42mA
-857.7mV  -24.54mA   -20.24mA   -31.91mA
-729.3mV  -15.9mA    -12.82mA   -20.86mA
-549.6mV  -5.951mA   -5.318mA   -7.644mA
-457.2mV  -2.687mA   -2.719mA   -3.292mA
-339.1mV  -694.8uA   -857.3uA   -789uA
3.55V     0A         0A         0A
[Power Clamp]
-1.756V   373.3mA    322.7mA    442.5mA
-1.161V   89.95mA    86.14mA    99.38mA
-1.14V    82.92mA    79.69mA    92.09mA
-1.115V   74.9mA     72.03mA    84.45mA
-1.063V   61.79mA    58.32mA    73.58mA
-996.8mV  50.38mA    44.26mA    64.33mA
-878.8mV  37.79mA    29.21mA    50.5mA
-755.6mV  26.89mA    20.06mA    36.52mA
-519.6mV  8.963mA    7.226mA    12.38mA
-411.9mV  3.293mA    3.168mA    4.353mA
-329.8mV  928.4uA    1.22mA     1.019mA
3.556V    0A         0A         0A
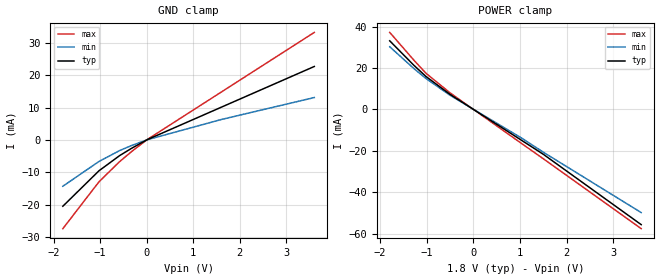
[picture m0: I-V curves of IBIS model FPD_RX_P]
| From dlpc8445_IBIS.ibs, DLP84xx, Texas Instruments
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|   Model RX_P
[Model] FPD_RX_P
Model_type Input
Polarity   Non-Inverting
Enable   Active-High
Vinl =  1.200V
Vinh =  1.300V
C_comp   0.131pF   0.123pF   0.134pF
C_comp_power_clamp   13.440fF   NA   19.534fF
[Model Spec]
Vinh   1.300V   1.300V   1.300V
Vinl   1.200V   1.200V   1.200V
[Temperature Range]   25.000   0.125k   -40.000
[Voltage Range]   1.800V   1.620V   1.980V
[POWER Clamp Reference]   1.800V   1.620V   1.980V
[GND Clamp Reference]   0.0V   0.0V   0.0V
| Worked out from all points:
|   GND clamp passes 1 mA (typ) near -0.13 V on its own axis
|   POWER clamp passes 1 mA (typ) near -0.07 V on its own axis
[GND_clamp]
|Voltage   I(typ)   I(min)   I(max)
-1.8V     -20.5mA    -14.32mA   -27.43mA
-1.023V   -9.529mA   -6.655mA   -12.93mA
-579mV    -4.84mA    -3.285mA   -6.686mA
-320mV    -2.565mA   -1.718mA   -3.565mA
13mV      81.94uA    51.08uA    120uA
1.604V    10.11mA    6.303mA    14.8mA
3.6V      22.69mA    13.09mA    33.22mA
[POWER_clamp]
|Voltage   I(typ)   I(min)   I(max)
-1.789V   33.11mA    30.25mA    37.17mA
-1.271V   21.3mA     19.74mA    23.77mA
-1.012V   15.91mA    14.93mA    17.46mA
-494mV    7.253mA    6.82mA     7.987mA
1.06V     -15.2mA    -14.1mA    -16.77mA
1.504V    -21.62mA   -20.61mA   -23.78mA
3.6V      -55.51mA   -49.7mA    -57.46mA
